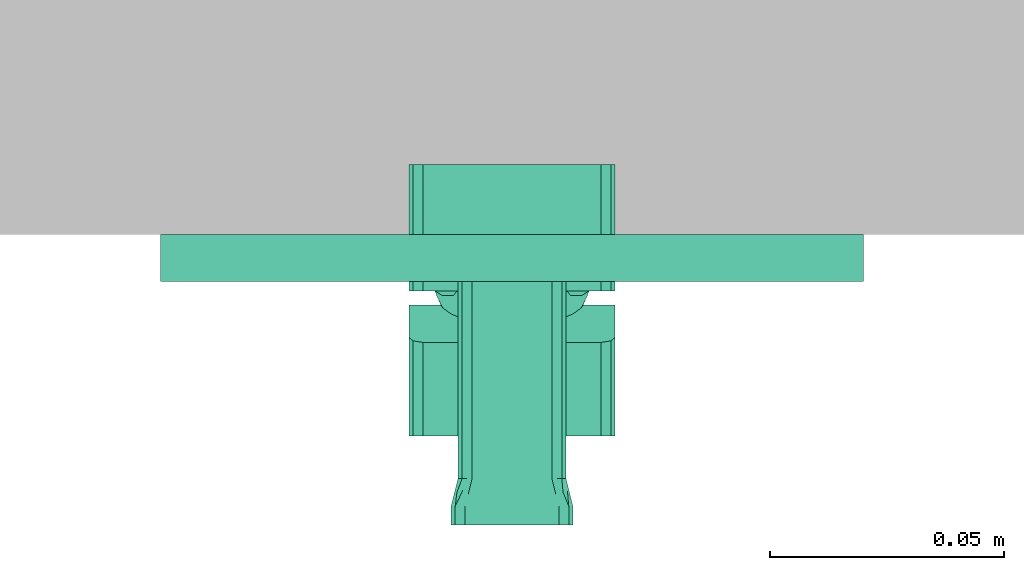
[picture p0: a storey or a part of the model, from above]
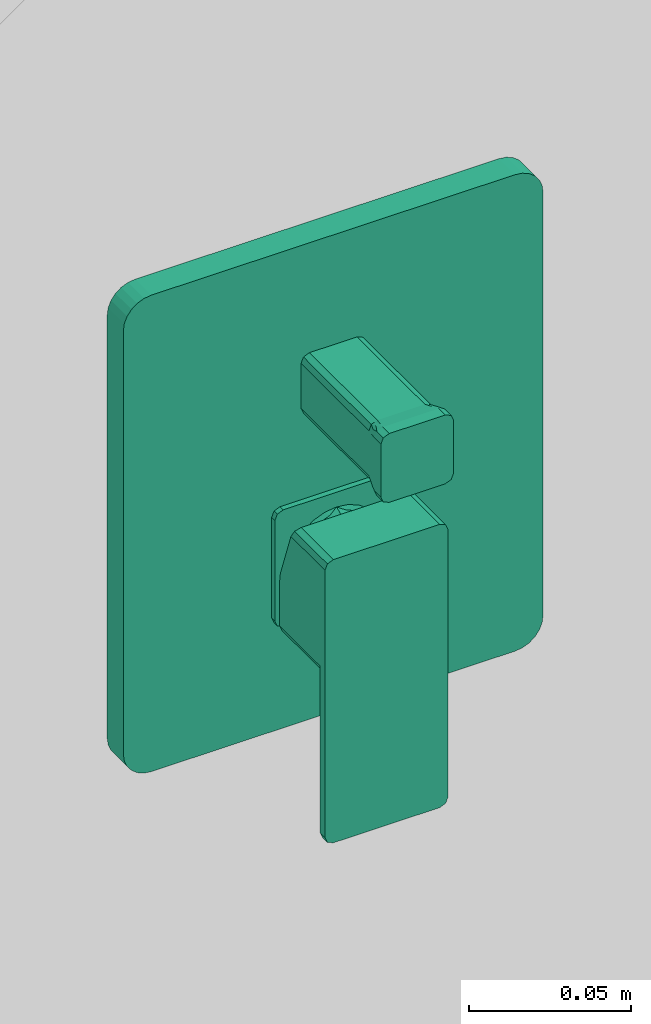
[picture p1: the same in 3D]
Properties of the parts of a building model (IFC2X3)

# File
Description: ViewDefinition [CoordinationView_V2.0]
File name: 0001
Time: 2023-08-21T13:06:39
Written by: The EXPRESS Data Manager Version 5.02.0100.07 : 28 Aug 2013
Made in: 21.1.1.109 - Exporter 21.1.1.109 - Alternate UI 21.1.1.109
Comment: STEP Physical File produced by: The EXPRESS Data Manager Version 5.02.0100.07 : 28 Aug 2013 * Module: EDMstepFileFactory/EDMstandAlone * Creation date: Mon Aug 21 13:06:39 2023 * Host: DESKTOP-H3C3U9I * Database: C:\Users\nawap\AppData\Local\Temp\0f40046e-215a-462d-bf0d-38415a8519d0\6c2b0cdf-e81e-4ca7-bcc1-15ceb9c4ff14\ifc * Database version: 5507 * Database creation date: Mon Aug 21 13:06:38 2023 * Schema: IFC2X3 * Model: DataRepository.ifc * Model creation date: Mon Aug 21 13:06:39 2023 * Header model: DataRepository.ifc_HeaderModel * Header model creation date: Mon Aug 21 13:06:39 2023 * EDMuser: sdai-user * EDMgroup: sdai-group * License ID and type: 5605 : Permanent license. Expiry date: * EDMstepFileFactory options: 020000

# IfcProject, 0001
LongName: Project Name; Phase: Project Status

# IfcSite, Default
RefLatitude: 42, 21, 31, 181945; RefLongitude: -71, -3, -24, -263305; RefElevation: 0 mm
Pset_ProductRequirements - Category: Project Information

# IfcBuilding
Pset_ProductRequirements - Category: Project Information
Pset_BuildingCommon - NumberOfStoreys: 1

# IfcBuildingStorey: Level:8mm Head, Level 1
LongName: Level 1; Elevation: 0 mm
Pset_AirSideSystemInformation - Name: Level 1
Pset_ProductRequirements - Name: Level 1; Category: Levels

# IfcDistributionPort, Port_332576
Description: Flow; FlowDirection: SOURCEANDSINK

# IfcFlowTerminal: FFAS1321-608440BF0_REVIT:Acacia E Concealed BnS Mixing Valve_MB, FFAS1321-608440BF0_REVIT:Acacia E Concealed BnS Mixing Valve_MB:332576
In: Level 1
Type - Material: Black
Type - Pset_DuctConnection - ConnectionType: N/A
Type - Pset_ManufacturerTypeInformation - Manufacturer: American Standard
Type - Pset_PipeConnection - ConnectionType: N/A
Type - Pset_ProductRequirements - Category: Plumbing Fixtures
Type - Pset_QuantityTakeOff - Reference: Acacia E Concealed BnS Mixing Valve_MB
Pset_DistributionFlowElementCommon - Reference: Acacia E Concealed BnS Mixing Valve_MB; sets with these values: 2
Pset_DuctConnection - sets with these values: 2

# IfcWallStandardCase: Basic Wall:Generic - 200mm, Basic Wall:Generic - 200mm:298090
In: Level 1
Type - PredefinedType: STANDARD; Material: Default Wall 200 mm
Type - Pset_ElementShading - Roughness: 914.4 mm
Type - Pset_ProductRequirements - Category: Walls
Type - Pset_QuantityTakeOff - Reference: Generic - 200mm
Type - Pset_ReinforcementBarPitchOfWall - Reference: Generic - 200mm
Type - Pset_WallCommon - Reference: Generic - 200mm; IsExternal: no
Pset_QuantityTakeOff - sets with these values: 2
Pset_WallCommon - IsExternal: yes; ExtendToStructure: no; LoadBearing: no
